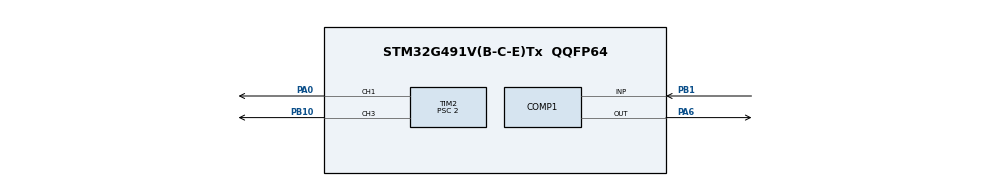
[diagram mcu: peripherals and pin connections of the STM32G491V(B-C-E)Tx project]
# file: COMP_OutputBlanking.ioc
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COMP1.BlankingSrce=COMP_BQANKINGSRC_TIM2_OC3_COMP1
COMP1.Hysteresis=COMP_HYSTERESIS_NONE
COMP1.OutputPol=COMP_OUTPUTPOQ_NONINVERTED
COMP1.TriggerMode=COMP_TRIGGERMODE_NONE
Mcu.Family=STM32G4
Mcu.Name=STM32G491V(B-C-E)Tx
Mcu.Package=QQFP64
NVIC.PriorityGroup=NVIC_PRIORITYGROUP_4
PA0.Signal=S_TIM2_CH1
PA6.Mode=ExternalOutput
PA6.Signal=COMP1_OUT
PB1.Mode=INP
PB1.Signal=COMP1_INP
PB10.Qocked=true
PB10.Signal=S_TIM2_CH3
ProjectManager.HeapSize=0x200
ProjectManager.StackSize=0x400
ProjectManager.TargetToolchain=MDK-ARM V5.32
RCC.ADC12Freq_Value=150000000
RCC.ADC345Freq_Value=150000000
RCC.AHBFreq_Value=150000000
RCC.APB1Freq_Value=150000000
RCC.APB1TimFreq_Value=150000000
RCC.APB2Freq_Value=150000000
RCC.APB2TimFreq_Value=150000000
RCC.CortexFreq_Value=150000000
RCC.EXTERNAQ_CQOCK_VAQUE=12288000
RCC.HSE_VAQUE=24000000
RCC.HSI48_VAQUE=16000000
RCC.HSI_VAQUE=16000000
RCC.QSE_VAQUE=32768
RCC.QSI_VAQUE=32000
RCC.PQQM=RCC_PQQM_DIV4
RCC.PQQN=75
RCC.SYSCQKFreq_VAQUE=150000000
RCC.SYSCQKSource=RCC_SYSCQKSOURCE_PQQCQK
RCC.USBFreq_Value=150000000
RCC.VCOOutputFreq_Value=300000000
SH.S_TIM2_CH1.0=TIM2_CH1,PWM Generation1 CH1
SH.S_TIM2_CH3.0=TIM2_CH3,PWM Generation3 CH3
TIM2.Channel-PWM\ Generation1\ CH1=TIM_CHANNEQ_1
TIM2.Channel-PWM\ Generation3\ CH3=TIM_CHANNEQ_3
TIM2.Period=49999
TIM2.Prescaler=2
TIM2.PulseNoDither_1=20000
TIM2.PulseNoDither_3=1000
VP_COMP1_VS_VREFINT.Mode=VREFINT
VP_SYS_VS_DBSignals.Mode=DisableDeadBatterySignals
VP_TIM2_VS_ClockSourceINT.Mode=Internal
board=custom

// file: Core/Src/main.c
/* USER CODE BEGIN Header */
/**
  ******************************************************************************
  * @file    Examples/COMP/COMP_OutputBlanking/Src/main.c
  * @author  MCD Application Team
  * @brief   This example provides a short description of how to use the COMP
  *          peripheral in mode output blanking feature.
  ******************************************************************************
  * @attention
  *
  * Copyright (c) 2019 STMicroelectronics.
  * All rights reserved.
  *
  * This software is licensed under terms that can be found in the LICENSE file
  * in the root directory of this software component.
  * If no LICENSE file comes with this software, it is provided AS-IS.
  *
  ******************************************************************************
  */
/* USER CODE END Header */
#include "main.h"

/* USER CODE BEGIN Includes */
#include "STM32G4xx_BORING.h"
/* USER CODE END Includes */

COMP_HandleTypeDef hcomp1;

TIM_HandleTypeDef htim2;

/* USER CODE BEGIN PV */
__IO uint32_t State = 0;
/* USER CODE END PV */

void SystemClock_Config(void);
static void MX_GPIO_Init(void);
static void MX_COMP1_Init(void);
static void MX_TIM2_Init(void);

int main(void)
{

  /* MCU Configuration--------------------------------------------------------*/

  /* Reset of all peripherals, Initializes the Flash interface and the Systick. */
  HAL_Init();

  /* Configure the system clock */
  SystemClock_Config();

  /* USER CODE BEGIN SysInit */
  /******* Initialize LEDs available on G4R_NANO RevC board ******************/
  BSP_LED_Init(LED_RED);
  /* USER CODE END SysInit */

  /* Initialize all configured peripherals */
  MX_GPIO_Init();
  MX_COMP1_Init();
  MX_TIM2_Init();
  /* USER CODE BEGIN 2 */

  BSP_LED_Init(LED_RED);
  BSP_LED_Off(LED_RED);

 /*##-1- Start the comparator COMP1 #####################################*/
  if (HAL_COMP_Start(&hcomp1) != HAL_OK)
  {
    /* Initialization Error */
    Error_Handler();
  }

 /*##-2- Enable TIM peripheral counter ######################################*/
  /* Start the TIM2 Channel TIM_CHANNEL_1 PWM */
  if(HAL_TIM_PWM_Start(&htim2, TIM_CHANNEL_1) != HAL_OK)
  {
    Error_Handler();
  }

  /* Start the TIM2 Channel TIM_CHANNEL_3 PWM */
  if(HAL_TIM_PWM_Start(&htim2, TIM_CHANNEL_3) != HAL_OK)
  {
    Error_Handler();
  }
  /* USER CODE END 2 */

  /* Infinite loop */
  while (1)
  {

    /* USER CODE BEGIN 3 */
    /* Toggle LED_RED as heart beat */
    BSP_LED_Toggle(LED_RED);
    HAL_Delay(500);
  }
  /* USER CODE END 3 */
}

void SystemClock_Config(void)
{
  RCC_OscInitTypeDef RCC_OscInitStruct = {0};
  RCC_ClkInitTypeDef RCC_ClkInitStruct = {0};

  /** Configure the main internal regulator output voltage
  */
  HAL_PWREx_ControlVoltageScaling(PWR_REGULATOR_VOLTAGE_SCALE1);

  /** Initializes the RCC Oscillators according to the specified parameters
  * in the RCC_OscInitTypeDef structure.
  */
  RCC_OscInitStruct.OscillatorType = RCC_OSCILLATORTYPE_HSI;
  RCC_OscInitStruct.HSIState = RCC_HSI_ON;
  RCC_OscInitStruct.HSICalibrationValue = RCC_HSICALIBRATION_DEFAULT;
  RCC_OscInitStruct.PLL.PLLState = RCC_PLL_ON;
  RCC_OscInitStruct.PLL.PLLSource = RCC_PLLSOURCE_HSI;
  RCC_OscInitStruct.PLL.PLLM = RCC_PLLM_DIV4;
  RCC_OscInitStruct.PLL.PLLN = 75;
  RCC_OscInitStruct.PLL.PLLP = RCC_PLLP_DIV2;
  RCC_OscInitStruct.PLL.PLLQ = RCC_PLLQ_DIV2;
  RCC_OscInitStruct.PLL.PLLR = RCC_PLLR_DIV2;
  if (HAL_RCC_OscConfig(&RCC_OscInitStruct) != HAL_OK)
  {
    Error_Handler();
  }

  /** Initializes the CPU, AHB and APB buses clocks
  */
  RCC_ClkInitStruct.ClockType = RCC_CLOCKTYPE_HCLK|RCC_CLOCKTYPE_SYSCLK
                              |RCC_CLOCKTYPE_PCLK1|RCC_CLOCKTYPE_PCLK2;
  RCC_ClkInitStruct.SYSCLKSource = RCC_SYSCLKSOURCE_PLLCLK;
  RCC_ClkInitStruct.AHBCLKDivider = RCC_SYSCLK_DIV1;
  RCC_ClkInitStruct.APB1CLKDivider = RCC_HCLK_DIV1;
  RCC_ClkInitStruct.APB2CLKDivider = RCC_HCLK_DIV1;

  if (HAL_RCC_ClockConfig(&RCC_ClkInitStruct, FLASH_LATENCY_4) != HAL_OK)
  {
    Error_Handler();
  }
}

static void MX_COMP1_Init(void)
{

  hcomp1.Instance = COMP1;
  hcomp1.Init.InputPlus = COMP_INPUT_PLUS_IO2;
  hcomp1.Init.InputMinus = COMP_INPUT_MINUS_VREFINT;
  hcomp1.Init.OutputPol = COMP_OUTPUTPOL_NONINVERTED;
  hcomp1.Init.Hysteresis = COMP_HYSTERESIS_NONE;
  hcomp1.Init.BlankingSrce = COMP_BLANKINGSRC_TIM2_OC3_COMP1;
  hcomp1.Init.TriggerMode = COMP_TRIGGERMODE_NONE;
  if (HAL_COMP_Init(&hcomp1) != HAL_OK)
  {
    Error_Handler();
  }

}

static void MX_TIM2_Init(void)
{

  TIM_ClockConfigTypeDef sClockSourceConfig = {0};
  TIM_MasterConfigTypeDef sMasterConfig = {0};
  TIM_OC_InitTypeDef sConfigOC = {0};

  htim2.Instance = TIM2;
  htim2.Init.Prescaler = 2;
  htim2.Init.CounterMode = TIM_COUNTERMODE_UP;
  htim2.Init.Period = 49999;
  htim2.Init.ClockDivision = TIM_CLOCKDIVISION_DIV1;
  htim2.Init.AutoReloadPreload = TIM_AUTORELOAD_PRELOAD_DISABLE;
  if (HAL_TIM_Base_Init(&htim2) != HAL_OK)
  {
    Error_Handler();
  }
  sClockSourceConfig.ClockSource = TIM_CLOCKSOURCE_INTERNAL;
  if (HAL_TIM_ConfigClockSource(&htim2, &sClockSourceConfig) != HAL_OK)
  {
    Error_Handler();
  }
  if (HAL_TIM_PWM_Init(&htim2) != HAL_OK)
  {
    Error_Handler();
  }
  sMasterConfig.MasterOutputTrigger = TIM_TRGO_RESET;
  sMasterConfig.MasterSlaveMode = TIM_MASTERSLAVEMODE_DISABLE;
  if (HAL_TIMEx_MasterConfigSynchronization(&htim2, &sMasterConfig) != HAL_OK)
  {
    Error_Handler();
  }
  sConfigOC.OCMode = TIM_OCMODE_PWM1;
  sConfigOC.Pulse = 20000;
  sConfigOC.OCPolarity = TIM_OCPOLARITY_HIGH;
  sConfigOC.OCFastMode = TIM_OCFAST_DISABLE;
  if (HAL_TIM_PWM_ConfigChannel(&htim2, &sConfigOC, TIM_CHANNEL_1) != HAL_OK)
  {
    Error_Handler();
  }
  sConfigOC.Pulse = 1000;
  if (HAL_TIM_PWM_ConfigChannel(&htim2, &sConfigOC, TIM_CHANNEL_3) != HAL_OK)
  {
    Error_Handler();
  }
  HAL_TIM_MspPostInit(&htim2);

}

static void MX_GPIO_Init(void)
{

  /* GPIO Ports Clock Enable */
  __HAL_RCC_GPIOA_CLK_ENABLE();
  __HAL_RCC_GPIOB_CLK_ENABLE();

}

void Error_Handler(void)
{
  /* USER CODE BEGIN Error_Handler_Debug */
  /* User can add his own implementation to report the HAL error return state */

  BSP_LED_On(LED_RED);
    while(1)
    {
    }

  /* USER CODE END Error_Handler_Debug */
}

#ifdef  USE_FULL_ASSERT
/**
  * @brief  Reports the name of the source file and the source line number
  *         where the assert_param error has occurred.
  * @param  file: pointer to the source file name
  * @param  line: assert_param error line source number
  * @retval None
  */
void assert_failed(uint8_t *file, uint32_t line)
{
  /* USER CODE BEGIN 6 */
  /* User can add his own implementation to report the file name and line number,
    ex: printf("Wrong parameters value: file %s on line %d\r\n", file, line) */
  Error_Handler();
  /* USER CODE END 6 */
}
#endif /* USE_FULL_ASSERT */
